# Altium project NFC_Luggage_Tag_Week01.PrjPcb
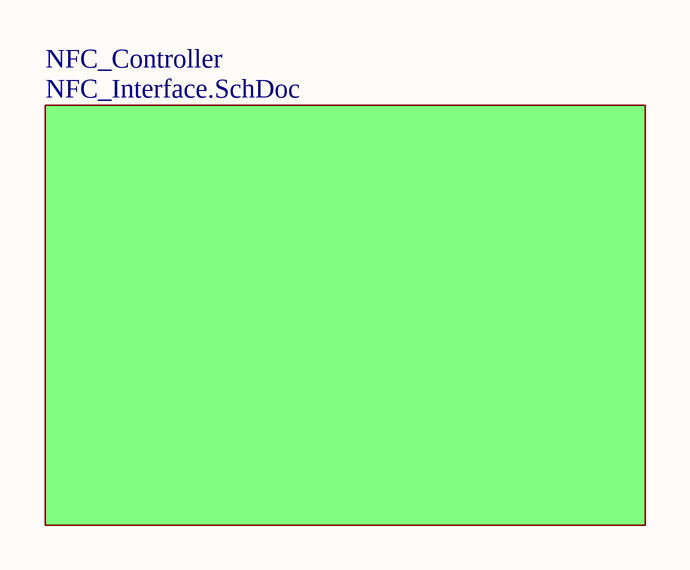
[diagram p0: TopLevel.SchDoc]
1 sheet, 0 parts. Net scope: global (net labels, ports and power ports of the same name join across sheets).

## Sheet TopLevel.SchDoc
size A4; SheetNumber: 1; SheetTotal: 1

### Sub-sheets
NFC_Controller = NFC_Interface.SchDoc (file not in this document): no entries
